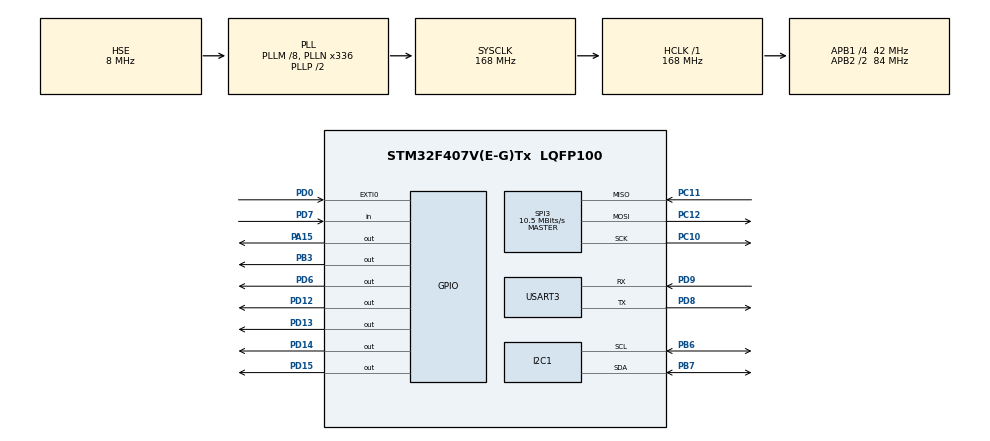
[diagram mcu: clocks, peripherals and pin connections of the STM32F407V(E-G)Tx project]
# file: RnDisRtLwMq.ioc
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Mcu.Family=STM32F4
PH0-OSC_IN.Signal=RCC_OSC_IN
RCC.CortexFreq_Value=168000000
SPI3.Direction=SPI_DIRECTION_2LINES
SPI3.VirtualType=VM_MASTER
PC10.Signal=SPI3_SCK
PC12.Signal=SPI3_MOSI
PD9.Mode=Asynchronous
RCC.SYSCLKSource=RCC_SYSCLKSOURCE_PLLCLK
ProjectManager.StackSize=0x400
PD13.Signal=GPIO_Output
RCC.HCLKFreq_Value=168000000
RCC.APB2TimFreq_Value=168000000
PB6.Signal=I2C1_SCL
PB6.Mode=I2C
PD0.Signal=GPXTI0
PD8.Signal=USART3_TX
RCC.AHBFreq_Value=168000000
PH0-OSC_IN.Mode=HSE-External-Oscillator
RCC.HSE_VALUE=8000000
PC14-OSC32_IN.Mode=LSE-External-Oscillator
NVIC.TIM2_IRQn=true\:0\:0\:false\:false\:true\:false\:false\:true
PB7.Signal=I2C1_SDA
VP_FREERTOS_VS_CMSIS_V1.Mode=CMSIS_V1
FREERTOS.configTOTAL_HEAP_SIZE=7*1024
PH1-OSC_OUT.Mode=HSE-External-Oscillator
Mcu.Package=LQFP100
VP_SYS_VS_tim2.Mode=TIM2
NVIC.TimeBase=TIM2_IRQn
SPI3.Mode=SPI_MODE_MASTER
PD12.Signal=GPIO_Output
NVIC.TimeBaseIP=TIM2
PA15.Signal=GPIO_Output
PC11.Mode=Full_Duplex_Master
RCC.APB2CLKDivider=RCC_HCLK_DIV2
RCC.APB1TimFreq_Value=84000000
PD6.Signal=GPIO_Output
PD15.Signal=GPIO_Output
VP_TIM3_VS_ClockSourceINT.Mode=Internal
RCC.PLLSourceVirtual=RCC_PLLSOURCE_HSE
PC15-OSC32_OUT.Mode=LSE-External-Oscillator
FREERTOS.Tasks01=defaultTask,0,128,StartDefaultTask,Default,NULL,Dynamic,NULL,NULL;Task2,-3,128,Start,Default,NULL,Dynamic,NULL,NULL
PC11.Signal=SPI3_MISO
PC10.Mode=Full_Duplex_Master
PD7.Signal=GPIO_Input
PD9.Signal=USART3_RX
RCC.APB1CLKDivider=RCC_HCLK_DIV4
PC14-OSC32_IN.Signal=RCC_OSC32_IN
ProjectManager.TargetToolchain=TrueSTUDIO
PC15-OSC32_OUT.Signal=RCC_OSC32_OUT
PD8.Mode=Asynchronous
PC12.Mode=Full_Duplex_Master
board=STM32F407G-DISC1
RCC.VCOOutputFreq_Value=336000000
NVIC.TIM3_IRQn=true\:5\:0\:false\:false\:true\:true\:true\:true
RCC.APB2Freq_Value=84000000
SPI3.CalculateBaudRate=10.5 MBits/s
SPI3.BaudRatePrescaler=SPI_BAUDRATEPRESCALER_4
PH1-OSC_OUT.Signal=RCC_OSC_OUT
Mcu.Name=STM32F407V(E-G)Tx
PD14.Signal=GPIO_Output
RCC.48MHZClocksFreq_Value=48000000
PB3.Signal=GPIO_Output
NVIC.EXTI0_IRQn=true\:5\:0\:false\:false\:true\:true\:true\:true
RCC.SYSCLKFreq_VALUE=168000000
PB5.Signal=I2C1_SMBA
USART3.VirtualMode=VM_ASYNC
PB7.Mode=I2C
ProjectManager.HeapSize=0x200
RCC.HSI_VALUE=16000000
VP_TIM4_VS_ClockSourceINT.Mode=Internal
RCC.PLLQ=7
NVIC.PriorityGroup=NVIC_PRIORITYGROUP_4
RCC.PLLM=8
RCC.PLLN=336
NVIC.TIM4_IRQn=true\:5\:0\:false\:false\:true\:true\:true\:true
RCC.APB1Freq_Value=42000000

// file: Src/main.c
/* USER CODE BEGIN Header */
/**
  ******************************************************************************
  * @file           : main.c
  * @brief          : Main program body
  ******************************************************************************
  * @attention
  *
  * <h2><center>&copy; Copyright (c) 2020 STMicroelectronics.
  * All rights reserved.</center></h2>
  *
  * This software component is licensed by ST under Ultimate Liberty license
  * SLA0044, the "License"; You may not use this file except in compliance with
  * the License. You may obtain a copy of the License at:
  *                             www.st.com/SLA0044
  *
  ******************************************************************************
  */
/* USER CODE END Header */

#include "main.h"
#include "cmsis_os.h"

/* USER CODE BEGIN Includes */
#include "lwip.h"
#include "ethernetif.h"
#include "app_ethernet.h"
#include "lwip/netif.h"
#include "lwip/tcpip.h"
#include "lwip/timeouts.h"
#include "lwip_mqtt.h"

/* USER CODE END Includes */

/* USER CODE BEGIN PM */
ip4_addr_t ipaddr;
ip4_addr_t netmask;
ip4_addr_t gw;
uint8_t IP_ADDRESS[4];
uint8_t NETMASK_ADDRESS[4];
uint8_t GATEWAY_ADDRESS[4];
/* USER CODE END PM */

I2C_HandleTypeDef hi2c1;

SPI_HandleTypeDef hspi3;

TIM_HandleTypeDef htim3;
TIM_HandleTypeDef htim4;

UART_HandleTypeDef huart3;

osThreadId defaultTaskHandle;
osThreadId Task2Handle;
/* USER CODE BEGIN PV */
struct netif gnetif; /* network interface structure */
char pacote[1000];
mqtt_client_t *client;
uint32_t counter=0,tiner=0;
struct netif gnetif; /* network interface structure */
/* Semaphore to signal Ethernet Link state update */
osSemaphoreId Netif_IRQSemaphore = NULL;

extern uint8_t check;
GPIO_InitTypeDef GPIO_InitStruct;
extern uint32_t timercounter;
/* Ethernet link thread Argument */
struct enc_irq_str irq_arg;
void MX_LWIP_Init(void);
#define DHT11_PIN GPIO_PIN_9
#define DHT11_PORT GPIOC
/* USER CODE END PV */

void SystemClock_Config(void);
static void MX_GPIO_Init(void);
static void MX_I2C1_Init(void);
static void MX_SPI3_Init(void);
static void MX_TIM3_Init(void);
static void MX_TIM4_Init(void);
static void MX_USART3_UART_Init(void);
void StartDefaultTask(void const * argument);
void Start(void const * argument);

/* USER CODE BEGIN PFP */
static void cloud_test(void const *arg);
/* USER CODE END PFP */

/* USER CODE BEGIN 0 */

uint8_t Rh_byte1, Rh_byte2, Temp_byte1, Temp_byte2;
uint16_t SUM, RH, TEMP;

float Temperature = 0;
float Humidity = 0;
uint8_t Presence = 0;

void Set_Pin_Output (GPIO_TypeDef *GPIOx, uint16_t GPIO_Pin)
{
	GPIO_InitTypeDef GPIO_InitStruct = {0};
	GPIO_InitStruct.Pin = GPIO_Pin;
	GPIO_InitStruct.Mode = GPIO_MODE_OUTPUT_PP;
	GPIO_InitStruct.Speed = GPIO_SPEED_FREQ_LOW;
	HAL_GPIO_Init(GPIOx, &GPIO_InitStruct);
}

void Set_Pin_Input (GPIO_TypeDef *GPIOx, uint16_t GPIO_Pin)
{
	GPIO_InitTypeDef GPIO_InitStruct = {0};
	GPIO_InitStruct.Pin = GPIO_Pin;
	GPIO_InitStruct.Mode = GPIO_MODE_INPUT;
	GPIO_InitStruct.Pull = GPIO_PULLUP;
	HAL_GPIO_Init(GPIOx, &GPIO_InitStruct);
}

void DHT11_Start (void)
{
	Set_Pin_Output (DHT11_PORT, DHT11_PIN);  // set the pin as output
	HAL_GPIO_WritePin (DHT11_PORT, DHT11_PIN, 0);   // pull the pin low
	delay (18000);   // wait for 18ms
    HAL_GPIO_WritePin (DHT11_PORT, DHT11_PIN, 1);   // pull the pin high
	delay (20);   // wait for 20us
	Set_Pin_Input(DHT11_PORT, DHT11_PIN);    // set as input
}

uint8_t DHT11_Check_Response (void)
{
	uint8_t Response = 0;
	delay (40);
	if (!(HAL_GPIO_ReadPin (DHT11_PORT, DHT11_PIN)))
	{
		delay (80);
		if ((HAL_GPIO_ReadPin (DHT11_PORT, DHT11_PIN))) Response = 1;
		else Response = -1; // 255
	}
	while ((HAL_GPIO_ReadPin (DHT11_PORT, DHT11_PIN)));   // wait for the pin to go low

	return Response;
}

uint8_t DHT11_Read (void)
{
	uint8_t i,j;
	for (j=0;j<8;j++)
	{
		while (!(HAL_GPIO_ReadPin (DHT11_PORT, DHT11_PIN)));   // wait for the pin to go high
		delay (40);   // wait for 40 us
		if (!(HAL_GPIO_ReadPin (DHT11_PORT, DHT11_PIN)))   // if the pin is low
		{
			i&= ~(1<<(7-j));   // write 0
		}
		else i|= (1<<(7-j));  // if the pin is high, write 1
		while ((HAL_GPIO_ReadPin (DHT11_PORT, DHT11_PIN)));  // wait for the pin to go low
	}
	return i;
}
void delay (uint16_t time)
{
	/* change your code here for the delay in microseconds */

	__HAL_TIM_SET_COUNTER(&htim4, 0);
	while ((__HAL_TIM_GET_COUNTER(&htim4))<time);}
/* USER CODE END 0 */

int main(void)
{

  /* MCU Configuration--------------------------------------------------------*/

  /* Reset of all peripherals, Initializes the Flash interface and the Systick. */
  HAL_Init();

  /* Configure the system clock */
  SystemClock_Config();

  /* Initialize all configured peripherals */
  MX_GPIO_Init();
  MX_I2C1_Init();
  MX_SPI3_Init();
  MX_TIM3_Init();
  MX_TIM4_Init();
  MX_USART3_UART_Init();

  /* Create the thread(s) */
  /* definition and creation of defaultTask */
 osThreadDef(defaultTask, StartDefaultTask, osPriorityNormal, 0, configMINIMAL_STACK_SIZE + 1000 );
 defaultTaskHandle = osThreadCreate(osThread(defaultTask), NULL);

  /* definition and creation of Task2 */
  osThreadDef(Task2, Start, osPriorityHigh, 0, 1024);
  Task2Handle = osThreadCreate(osThread(Task2), NULL);

  /* Start scheduler */
  osKernelStart();

  /* We should never get here as control is now taken by the scheduler */
  /* Infinite loop */
  while (1)
  {

  }
}

void SystemClock_Config(void)
{
  RCC_OscInitTypeDef RCC_OscInitStruct = {0};
  RCC_ClkInitTypeDef RCC_ClkInitStruct = {0};

  /** Configure the main internal regulator output voltage
  */
  __HAL_RCC_PWR_CLK_ENABLE();
  __HAL_PWR_VOLTAGESCALING_CONFIG(PWR_REGULATOR_VOLTAGE_SCALE1);
  /** Initializes the CPU, AHB and APB busses clocks
  */
  RCC_OscInitStruct.OscillatorType = RCC_OSCILLATORTYPE_HSE;
  RCC_OscInitStruct.HSEState = RCC_HSE_ON;
  RCC_OscInitStruct.PLL.PLLState = RCC_PLL_ON;
  RCC_OscInitStruct.PLL.PLLSource = RCC_PLLSOURCE_HSE;
  RCC_OscInitStruct.PLL.PLLM = 8;
  RCC_OscInitStruct.PLL.PLLN = 336;
  RCC_OscInitStruct.PLL.PLLP = RCC_PLLP_DIV2;
  RCC_OscInitStruct.PLL.PLLQ = 7;
  if (HAL_RCC_OscConfig(&RCC_OscInitStruct) != HAL_OK)
  {
    Error_Handler();
  }
  /** Initializes the CPU, AHB and APB busses clocks
  */
  RCC_ClkInitStruct.ClockType = RCC_CLOCKTYPE_HCLK|RCC_CLOCKTYPE_SYSCLK
                              |RCC_CLOCKTYPE_PCLK1|RCC_CLOCKTYPE_PCLK2;
  RCC_ClkInitStruct.SYSCLKSource = RCC_SYSCLKSOURCE_PLLCLK;
  RCC_ClkInitStruct.AHBCLKDivider = RCC_SYSCLK_DIV1;
  RCC_ClkInitStruct.APB1CLKDivider = RCC_HCLK_DIV4;
  RCC_ClkInitStruct.APB2CLKDivider = RCC_HCLK_DIV2;

  if (HAL_RCC_ClockConfig(&RCC_ClkInitStruct, FLASH_LATENCY_5) != HAL_OK)
  {
    Error_Handler();
  }
}

static void MX_I2C1_Init(void)
{

  hi2c1.Instance = I2C1;
  hi2c1.Init.ClockSpeed = 100000;
  hi2c1.Init.DutyCycle = I2C_DUTYCYCLE_2;
  hi2c1.Init.OwnAddress1 = 0;
  hi2c1.Init.AddressingMode = I2C_ADDRESSINGMODE_7BIT;
  hi2c1.Init.DualAddressMode = I2C_DUALADDRESS_DISABLE;
  hi2c1.Init.OwnAddress2 = 0;
  hi2c1.Init.GeneralCallMode = I2C_GENERALCALL_DISABLE;
  hi2c1.Init.NoStretchMode = I2C_NOSTRETCH_DISABLE;
  if (HAL_I2C_Init(&hi2c1) != HAL_OK)
  {
    Error_Handler();
  }

}

static void MX_SPI3_Init(void)
{

  /* SPI3 parameter configuration*/
  hspi3.Instance = SPI3;
  hspi3.Init.Mode = SPI_MODE_MASTER;
  hspi3.Init.Direction = SPI_DIRECTION_2LINES;
  hspi3.Init.DataSize = SPI_DATASIZE_8BIT;
  hspi3.Init.CLKPolarity = SPI_POLARITY_LOW;
  hspi3.Init.CLKPhase = SPI_PHASE_1EDGE;
  hspi3.Init.NSS = SPI_NSS_SOFT;
  hspi3.Init.BaudRatePrescaler = SPI_BAUDRATEPRESCALER_4;
  hspi3.Init.FirstBit = SPI_FIRSTBIT_MSB;
  hspi3.Init.TIMode = SPI_TIMODE_DISABLE;
  hspi3.Init.CRCCalculation = SPI_CRCCALCULATION_DISABLE;
  hspi3.Init.CRCPolynomial = 10;
  if (HAL_SPI_Init(&hspi3) != HAL_OK)
  {
    Error_Handler();
  }

}

static void MX_TIM3_Init(void)
{

  TIM_ClockConfigTypeDef sClockSourceConfig = {0};
  TIM_MasterConfigTypeDef sMasterConfig = {0};

  htim3.Instance = TIM3;
  htim3.Init.Prescaler = 83;
  htim3.Init.CounterMode = TIM_COUNTERMODE_UP;
  htim3.Init.Period = 999;
  htim3.Init.ClockDivision = TIM_CLOCKDIVISION_DIV1;
  htim3.Init.AutoReloadPreload = TIM_AUTORELOAD_PRELOAD_DISABLE;
  if (HAL_TIM_Base_Init(&htim3) != HAL_OK)
  {
    Error_Handler();
  }
  sClockSourceConfig.ClockSource = TIM_CLOCKSOURCE_INTERNAL;
  if (HAL_TIM_ConfigClockSource(&htim3, &sClockSourceConfig) != HAL_OK)
  {
    Error_Handler();
  }
  sMasterConfig.MasterOutputTrigger = TIM_TRGO_RESET;
  sMasterConfig.MasterSlaveMode = TIM_MASTERSLAVEMODE_DISABLE;
  if (HAL_TIMEx_MasterConfigSynchronization(&htim3, &sMasterConfig) != HAL_OK)
  {
    Error_Handler();
  }

}

static void MX_TIM4_Init(void)
{

  TIM_ClockConfigTypeDef sClockSourceConfig = {0};
  TIM_MasterConfigTypeDef sMasterConfig = {0};

  htim4.Instance = TIM4;
  htim4.Init.Prescaler = 83;
  htim4.Init.CounterMode = TIM_COUNTERMODE_UP;
  htim4.Init.Period = 0xffff;
  htim4.Init.ClockDivision = TIM_CLOCKDIVISION_DIV1;
  htim4.Init.AutoReloadPreload = TIM_AUTORELOAD_PRELOAD_DISABLE;
  if (HAL_TIM_Base_Init(&htim4) != HAL_OK)
  {
    Error_Handler();
  }
  sClockSourceConfig.ClockSource = TIM_CLOCKSOURCE_INTERNAL;
  if (HAL_TIM_ConfigClockSource(&htim4, &sClockSourceConfig) != HAL_OK)
  {
    Error_Handler();
  }
  sMasterConfig.MasterOutputTrigger = TIM_TRGO_RESET;
  sMasterConfig.MasterSlaveMode = TIM_MASTERSLAVEMODE_DISABLE;
  if (HAL_TIMEx_MasterConfigSynchronization(&htim4, &sMasterConfig) != HAL_OK)
  {
    Error_Handler();
  }

}

static void MX_USART3_UART_Init(void)
{

  huart3.Instance = USART3;
  huart3.Init.BaudRate = 115200;
  huart3.Init.WordLength = UART_WORDLENGTH_8B;
  huart3.Init.StopBits = UART_STOPBITS_1;
  huart3.Init.Parity = UART_PARITY_NONE;
  huart3.Init.Mode = UART_MODE_TX_RX;
  huart3.Init.HwFlowCtl = UART_HWCONTROL_NONE;
  huart3.Init.OverSampling = UART_OVERSAMPLING_16;
  if (HAL_UART_Init(&huart3) != HAL_OK)
  {
    Error_Handler();
  }

}

static void MX_GPIO_Init(void)
{
  GPIO_InitTypeDef GPIO_InitStruct = {0};

  /* GPIO Ports Clock Enable */
  __HAL_RCC_GPIOC_CLK_ENABLE();
  __HAL_RCC_GPIOH_CLK_ENABLE();
  __HAL_RCC_GPIOD_CLK_ENABLE();
  __HAL_RCC_GPIOA_CLK_ENABLE();
  __HAL_RCC_GPIOB_CLK_ENABLE();

  /*Configure GPIO pin Output Level */
  HAL_GPIO_WritePin(GPIOD, GPIO_PIN_12|GPIO_PIN_13|GPIO_PIN_14|GPIO_PIN_15
                          |GPIO_PIN_6, GPIO_PIN_RESET);

  /*Configure GPIO pin Output Level */
  HAL_GPIO_WritePin(GPIOA, GPIO_PIN_15, GPIO_PIN_RESET);

  /*Configure GPIO pin Output Level */
  HAL_GPIO_WritePin(GPIOB, GPIO_PIN_3, GPIO_PIN_RESET);

  /*Configure GPIO pins : PD12 PD13 PD14 PD15
                           PD6 */
  GPIO_InitStruct.Pin = GPIO_PIN_12|GPIO_PIN_13|GPIO_PIN_14|GPIO_PIN_15
                          |GPIO_PIN_6;
  GPIO_InitStruct.Mode = GPIO_MODE_OUTPUT_PP;
  GPIO_InitStruct.Pull = GPIO_NOPULL;
  GPIO_InitStruct.Speed = GPIO_SPEED_FREQ_LOW;
  HAL_GPIO_Init(GPIOD, &GPIO_InitStruct);

  /*Configure GPIO pin : PA15 */
  GPIO_InitStruct.Pin = GPIO_PIN_15;
  GPIO_InitStruct.Mode = GPIO_MODE_OUTPUT_PP;
  GPIO_InitStruct.Pull = GPIO_NOPULL;
  GPIO_InitStruct.Speed = GPIO_SPEED_FREQ_LOW;
  HAL_GPIO_Init(GPIOA, &GPIO_InitStruct);

  /*Configure GPIO pin : PD0 */
  GPIO_InitStruct.Pin = GPIO_PIN_0;
  GPIO_InitStruct.Mode = GPIO_MODE_IT_RISING;
  GPIO_InitStruct.Pull = GPIO_NOPULL;
  HAL_GPIO_Init(GPIOD, &GPIO_InitStruct);

  /*Configure GPIO pin : PD7 */
  GPIO_InitStruct.Pin = GPIO_PIN_7;
  GPIO_InitStruct.Mode = GPIO_MODE_INPUT;
  GPIO_InitStruct.Pull = GPIO_NOPULL;
  HAL_GPIO_Init(GPIOD, &GPIO_InitStruct);

  /*Configure GPIO pin : PB3 */
  GPIO_InitStruct.Pin = GPIO_PIN_3;
  GPIO_InitStruct.Mode = GPIO_MODE_OUTPUT_PP;
  GPIO_InitStruct.Pull = GPIO_NOPULL;
  GPIO_InitStruct.Speed = GPIO_SPEED_FREQ_LOW;
  HAL_GPIO_Init(GPIOB, &GPIO_InitStruct);
  GPIO_InitStruct.Pin = GPIO_PIN_7;
   GPIO_InitStruct.Mode = GPIO_MODE_INPUT;
   GPIO_InitStruct.Pull = GPIO_NOPULL;
   HAL_GPIO_Init(GPIOC, &GPIO_InitStruct);
   GPIO_InitStruct.Pin = GPIO_PIN_9;
     GPIO_InitStruct.Mode = GPIO_MODE_OUTPUT_PP;
     GPIO_InitStruct.Pull = GPIO_NOPULL;
     GPIO_InitStruct.Speed = GPIO_SPEED_FREQ_HIGH;
     HAL_GPIO_Init(GPIOC, &GPIO_InitStruct);

  /* EXTI interrupt init*/
  HAL_NVIC_SetPriority(EXTI0_IRQn, 5, 0);
  HAL_NVIC_EnableIRQ(EXTI0_IRQn);

}

/* USER CODE BEGIN 4 */
void HAL_GPIO_EXTI_Callback(uint16_t GPIO_Pin)
{
//  /* Get the IT status register value */
//  if(BSP_IO_ITGetStatus(MII_INT_PIN))
  if (GPIO_Pin == ENC_INT_PIN)
  {
   ethernetif_set_link(&gnetif);
	 // ethernet_irq_handler(Netif_IRQSemaphore);

  }
  //BSP_IO_ITClear();
}

static void Mqtt_test(void const *arg)
{
	  MX_LWIP_Init();
		  User_notification(&gnetif);
		  client = mqtt_client_new();
		 if(client != NULL) {
		    sprintf(pacote,"hello_mohamed");
		     example_do_connect(client, "some_topic");
		     example_publish(client, pacote);
		 }
		   if(HAL_TIM_Base_Init(&htim3) != HAL_OK)
		   {
		     /* Initialization Error */
		     Error_Handler();
		   }

		   /*##-2- Start the TIM Base generation in interrupt mode ####################*/
		   /* Start Channel1 */
		   if(HAL_TIM_Base_Start_IT(&htim3) != HAL_OK)
		   {
		     /* Starting Error */
		     Error_Handler();
		   }
		   while(1){
				  osDelay(1);
		  ethernetif_input(&gnetif);
				    /* Triggers actual ethernet transmission if transmission buffers are not empty */
				   ethernet_transmit();
				   if(counter>799){
				  	   counter =0;
				  if(client != NULL) {
				   tiner=123;
				   example_do_connect(client, "hello_world");
				   sprintf(pacote,"{\"device_id\":%d,\"temperature\":%d.%d,\"Humiduty\":%d.%d,\"Led1\":1}",tiner,Temp_byte1,Temp_byte2,Rh_byte1,Rh_byte2);
				   example_publish(client, pacote);
				    }
				   }
		   }
}
/* USER CODE END 4 */

void StartDefaultTask(void const * argument)
{
  /* USER CODE BEGIN 5 */

osThreadDef(MQTTNAME, &Mqtt_test, osPriorityNormal, 0, 7 *1024);
osThreadCreate (osThread(MQTTNAME), NULL);
  /* Infinite loop */
  for(;;)
  {
   osThreadTerminate(NULL);

  /* USER CODE END 5 */
}
}
/* USER CODE BEGIN Header_Start */

void MX_LWIP_Init(void)
{
  /* IP addresses initialization */
  IP_ADDRESS[0] = 169;
  IP_ADDRESS[1] = 254;
  IP_ADDRESS[2] = 193;
  IP_ADDRESS[3] = 12;
  NETMASK_ADDRESS[0] = 255;
  NETMASK_ADDRESS[1] = 255;
  NETMASK_ADDRESS[2] = 0;
  NETMASK_ADDRESS[3] = 0;
  GATEWAY_ADDRESS[0] = 169;
  GATEWAY_ADDRESS[1] = 254;
  GATEWAY_ADDRESS[2] = 193;
  GATEWAY_ADDRESS[3] = 90;

  /* Initilialize the LwIP stack with RTOS */
  tcpip_init( NULL, NULL );

  IP4_ADDR(&ipaddr, IP_ADDR0, IP_ADDR1, IP_ADDR2, IP_ADDR3);
  IP4_ADDR(&netmask, NETMASK_ADDR0, NETMASK_ADDR1 , NETMASK_ADDR2, NETMASK_ADDR3);
  IP4_ADDR(&gw, GW_ADDR0, GW_ADDR1, GW_ADDR2, GW_ADDR3);
  /* create a binary semaphore used for informing ethernetif of frame reception */
//  osSemaphoreDef(Netif_SEM);
//  Netif_IRQSemaphore = osSemaphoreCreate(osSemaphore(Netif_SEM) , 1);

  /* add the network interface (IPv4/IPv6) with RTOS */
  netif_add(&gnetif, &ipaddr, &netmask, &gw, NULL, &ethernetif_init, &tcpip_input);

  /* Registers the default network interface */
  netif_set_default(&gnetif);

  if (netif_is_link_up(&gnetif))
  {
    /* When the netif is fully configured this function must be called */
    netif_set_up(&gnetif);
  }
  else
  {
    /* When the netif link is down this function must be called */
    netif_set_down(&gnetif);
  }
  netif_set_link_callback(&gnetif, ethernetif_update_config);

/* USER CODE BEGIN 3 */

	 //  irq_arg.netif = &gnetif;
	 //irq_arg.semaphore = Netif_IRQSemaphore;
  /* Create the Ethernet IRQ handler thread */
	 // osThreadDef(IrqThr, ethernetif_process_irq, osPriorityRealtime, 0, configMINIMAL_STACK_SIZE * 3);

	 // osThreadCreate (osThread(IrqThr), &irq_arg);
/* USER CODE END 3 */
}
/**
* @brief Function implementing the Task2 thread.
* @param argument: Not used
* @retval None
*/
/* USER CODE END Header_Start */
void Start(void const * argument)
{
  /* USER CODE BEGIN Start */
    char buffer[500];
		  if(HAL_TIM_Base_Init(&htim4) != HAL_OK)
		  {
		    /* Initialization Error */
		    Error_Handler();
		  }
HAL_TIM_Base_Start(&htim4);
sprintf(buffer,"here dht11_task\n\r");
HAL_UART_Transmit(&huart3,buffer,strlen(buffer),1000);
  /* Infinite loop */
  for(;;)
  {
	  DHT11_Start();
      Presence = DHT11_Check_Response();
	  Rh_byte1 = DHT11_Read ();
	  Rh_byte2 = DHT11_Read ();
	  Temp_byte1 = DHT11_Read ();
	  Temp_byte2 = DHT11_Read ();
	  SUM = DHT11_Read();
	  TEMP = Temp_byte1;
	  RH = Rh_byte1;
	  //Temperature = (float) TEMP;
	 // Humidity = (float) RH;
	  sprintf(buffer,"temp=%d.%d hum=%d.%d\n\r",Temp_byte1,Temp_byte2,Rh_byte1,Rh_byte2);
	  HAL_UART_Transmit(&huart3,buffer,strlen(buffer),1000);
//     platform_init()	subscribe_publish_sensor_values();
      osDelay(1100);

	  	//	   osThreadTerminate(NULL);
  }
  /* USER CODE END Start */
}

 /**
  * @brief  Period elapsed callback in non blocking mode
  * @note   This function is called  when TIM2 interrupt took place, inside
  * HAL_TIM_IRQHandler(). It makes a direct call to HAL_IncTick() to increment
  * a global variable "uwTick" used as application time base.
  * @param  htim : TIM handle
  * @retval None
  */
void HAL_TIM_PeriodElapsedCallback(TIM_HandleTypeDef *htim)
{
  if (htim->Instance == TIM2) {
    HAL_IncTick();
  }
  /* USER CODE BEGIN Callback 1 */
  if (htim->Instance == TIM3) {
   counter++;

  }

  /* USER CODE END Callback 1 */
}

void Error_Handler(void)
{
}

/************************ (C) COPYRIGHT STMicroelectronics *****END OF FILE****/
